One B-rep face of a CAD part: STEP entity #405.
In plain terms, the planar face has unit normal (1, 0, 0).
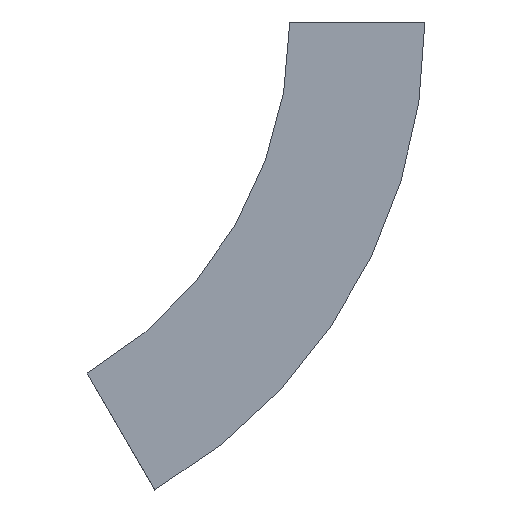
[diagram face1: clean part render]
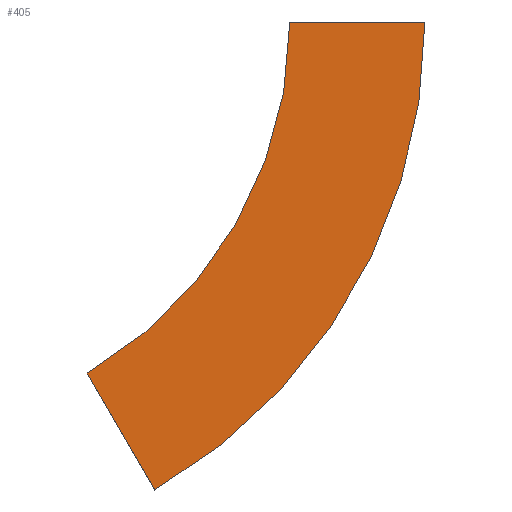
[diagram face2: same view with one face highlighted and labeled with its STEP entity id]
Its self-contained STEP definition (entity closure, numbers rounded to 3 decimals):
#20 = VERTEX_POINT ( 'NONE', #154 ) ;
#33 = CARTESIAN_POINT ( 'NONE',  ( 0., 300., 0. ) ) ;
#35 = AXIS2_PLACEMENT_3D ( 'NONE', #147, #540, #455 ) ;
#107 = CIRCLE ( 'NONE', #459, 400. ) ;
#111 = VECTOR ( 'NONE', #571, 1000. ) ;
#114 = VERTEX_POINT ( 'NONE', #255 ) ;
#117 = ORIENTED_EDGE ( 'NONE', *, *, #496, .T. ) ;
#144 = CARTESIAN_POINT ( 'NONE',  ( 0., -100., 0. ) ) ;
#147 = CARTESIAN_POINT ( 'NONE',  ( 0., -100., 0. ) ) ;
#149 = EDGE_CURVE ( 'NONE', #433, #114, #219, .T. ) ;
#154 = CARTESIAN_POINT ( 'NONE',  ( 0., 100., -346.41 ) ) ;
#159 = EDGE_CURVE ( 'NONE', #114, #270, #510, .T. ) ;
#187 = CARTESIAN_POINT ( 'NONE',  ( 0., 300., 0. ) ) ;
#196 = EDGE_LOOP ( 'NONE', ( #476, #508, #117, #483 ) ) ;
#219 = LINE ( 'NONE', #565, #111 ) ;
#221 = DIRECTION ( 'NONE',  ( 0., -1., 0. ) ) ;
#233 = FACE_OUTER_BOUND ( 'NONE', #196, .T. ) ;
#255 = CARTESIAN_POINT ( 'NONE',  ( 0., 0., 0. ) ) ;
#257 = LINE ( 'NONE', #266, #505 ) ;
#266 = CARTESIAN_POINT ( 'NONE',  ( 0., 100., -346.41 ) ) ;
#267 = AXIS2_PLACEMENT_3D ( 'NONE', #33, #400, #221 ) ;
#270 = VERTEX_POINT ( 'NONE', #411 ) ;
#306 = EDGE_CURVE ( 'NONE', #20, #270, #257, .T. ) ;
#368 = DIRECTION ( 'NONE',  ( 0., -1., 0. ) ) ;
#400 = DIRECTION ( 'NONE',  ( 1., 0., 0. ) ) ;
#405 = ADVANCED_FACE ( 'NONE', ( #233 ), #551, .F. ) ;
#411 = CARTESIAN_POINT ( 'NONE',  ( 0., 150., -259.808 ) ) ;
#419 = DIRECTION ( 'NONE',  ( 1., 0., 0. ) ) ;
#433 = VERTEX_POINT ( 'NONE', #144 ) ;
#453 = DIRECTION ( 'NONE',  ( 0., 0.5, 0.866 ) ) ;
#455 = DIRECTION ( 'NONE',  ( 0., 0., 1. ) ) ;
#459 = AXIS2_PLACEMENT_3D ( 'NONE', #187, #419, #368 ) ;
#476 = ORIENTED_EDGE ( 'NONE', *, *, #159, .F. ) ;
#483 = ORIENTED_EDGE ( 'NONE', *, *, #306, .T. ) ;
#496 = EDGE_CURVE ( 'NONE', #433, #20, #107, .T. ) ;
#505 = VECTOR ( 'NONE', #453, 1000. ) ;
#508 = ORIENTED_EDGE ( 'NONE', *, *, #149, .F. ) ;
#510 = CIRCLE ( 'NONE', #267, 300. ) ;
#540 = DIRECTION ( 'NONE',  ( -1., 0., 0. ) ) ;
#551 = PLANE ( 'NONE',  #35 ) ;
#565 = CARTESIAN_POINT ( 'NONE',  ( 0., -100., 0. ) ) ;
#571 = DIRECTION ( 'NONE',  ( 0., 1., 0. ) ) ;
